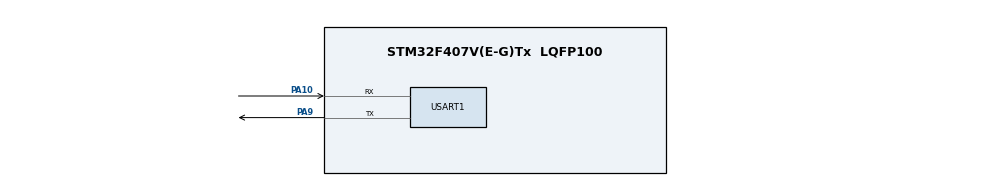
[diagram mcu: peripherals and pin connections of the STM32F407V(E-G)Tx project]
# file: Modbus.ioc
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Mcu.Family=STM32F4
Mcu.Name=STM32F407V(E-G)Tx
Mcu.Package=LQFP100
NVIC.PriorityGroup=NVIC_PRIORITYGROUP_4
NVIC.USART1_IRQn=true\:0\:0\:false\:false\:true\:true\:true\:true
PA10.Mode=Asynchronous
PA10.Signal=USART1_RX
PA13.Mode=Serial_Wire
PA13.Signal=SYS_JTMS-SWDIO
PA14.Mode=Serial_Wire
PA14.Signal=SYS_JTCK-SWCLK
PA9.Mode=Asynchronous
PA9.Signal=USART1_TX
PH0-OSC_IN.Mode=HSE-External-Oscillator
PH0-OSC_IN.Signal=RCC_OSC_IN
PH1-OSC_OUT.Mode=HSE-External-Oscillator
PH1-OSC_OUT.Signal=RCC_OSC_OUT
ProjectManager.HeapSize=0x200
ProjectManager.StackSize=0x400
ProjectManager.TargetToolchain=STM32CubeIDE
RCC.48MHZClocksFreq_Value=84000000
RCC.AHBFreq_Value=168000000
RCC.APB1CLKDivider=RCC_HCLK_DIV4
RCC.APB1Freq_Value=42000000
RCC.APB1TimFreq_Value=84000000
RCC.APB2CLKDivider=RCC_HCLK_DIV2
RCC.APB2Freq_Value=84000000
RCC.APB2TimFreq_Value=168000000
RCC.CortexFreq_Value=168000000
RCC.HCLKFreq_Value=168000000
RCC.HSE_VALUE=25000000
RCC.HSI_VALUE=16000000
RCC.LSE_VALUE=32768
RCC.PLLM=25
RCC.PLLN=336
RCC.PLLSourceVirtual=RCC_PLLSOURCE_HSE
RCC.SYSCLKFreq_VALUE=168000000
RCC.SYSCLKSource=RCC_SYSCLKSOURCE_PLLCLK
RCC.VCOOutputFreq_Value=336000000
USART1.VirtualMode=VM_ASYNC
board=custom

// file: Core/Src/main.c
/* USER CODE BEGIN Header */
/**
 ******************************************************************************
 * @file           : main.c
 * @brief          : Main program body
 ******************************************************************************
 * @attention
 *
 * Copyright (c) 2022 STMicroelectronics.
 * All rights reserved.
 *
 * This software is licensed under terms that can be found in the LICENSE file
 * in the root directory of this software component.
 * If no LICENSE file comes with this software, it is provided AS-IS.
 *
 ******************************************************************************
 */
/* USER CODE END Header */
#include "main.h"

void SystemClock_Config(void);
static void MX_GPIO_Init(void);
static void MX_USART1_UART_Init(void);
volatile int x=0;
/* USER CODE BEGIN PFP */
/* === Callback người dùng định nghĩa === */
void Timer6_Callback_1ms(void)
{
	//x++;
	  //Axis_TaskUpdate();
//    static uint8_t modbus_cnt = 0;

//    // gọi Modbus_TaskUpdate() mỗi 10 ms
//    if (++modbus_cnt >= 10)
//    {
//        modbus_cnt = 0;
//        Modbus_TaskUpdate();
//    }
    //Modbus_TaskUpdate();
    // nếu bạn muốn thêm task khác, có thể thêm ở đây
    // ví dụ:
    // if (++something >= 1000) { something = 0; blinkLED(); }
}
/* USER CODE END PFP */

int main(void)
{

  /* MCU Configuration--------------------------------------------------------*/

  /* Reset of all peripherals, Initializes the Flash interface and the Systick. */
  HAL_Init();

  /* Configure the system clock */
  SystemClock_Config();

  /* Initialize all configured peripherals */
  MX_GPIO_Init();
  MX_USART1_UART_Init();
  /* USER CODE BEGIN 2 */
  io_init();
  tim2_init();
  tim3_init();
  //TIM6_Init_1ms();
  Global_Timer_Init();
  Modbus_TaskInit(&huart1);
  /* USER CODE END 2 */

  /* Infinite loop */
  /* USER CODE BEGIN WHILE */
  Axis_Init(Holding_Registers_Database);
  HAL_Delay(1000);
  //Home_All();
  Axis_Home();
  while (1)
  {
    /* USER CODE END WHILE */
    /* USER CODE BEGIN 3 */
	  if (Task_RunEvery(1))	  Modbus_TaskUpdate();   // 1 ms
	  Axis_TaskUpdate();
  }
  /* USER CODE END 3 */
}

void SystemClock_Config(void)
{
  RCC_OscInitTypeDef RCC_OscInitStruct = {0};
  RCC_ClkInitTypeDef RCC_ClkInitStruct = {0};

  /** Configure the main internal regulator output voltage
   */
  __HAL_RCC_PWR_CLK_ENABLE();
  __HAL_PWR_VOLTAGESCALING_CONFIG(PWR_REGULATOR_VOLTAGE_SCALE1);

  /** Initializes the RCC Oscillators according to the specified parameters
   * in the RCC_OscInitTypeDef structure.
   */
  RCC_OscInitStruct.OscillatorType = RCC_OSCILLATORTYPE_HSE;
  RCC_OscInitStruct.HSEState = RCC_HSE_ON;
  RCC_OscInitStruct.PLL.PLLState = RCC_PLL_ON;
  RCC_OscInitStruct.PLL.PLLSource = RCC_PLLSOURCE_HSE;
#ifdef Tuan_board
  RCC_OscInitStruct.PLL.PLLM = 4;
  RCC_OscInitStruct.PLL.PLLN = 168;
#endif
#ifdef Chuc_board
  RCC_OscInitStruct.PLL.PLLM = 25;
  RCC_OscInitStruct.PLL.PLLN = 336;
#endif
  RCC_OscInitStruct.PLL.PLLP = RCC_PLLP_DIV2;
  RCC_OscInitStruct.PLL.PLLQ = 4;
  if (HAL_RCC_OscConfig(&RCC_OscInitStruct) != HAL_OK)
  {
    Error_Handler();
  }

  /** Initializes the CPU, AHB and APB buses clocks
   */
  RCC_ClkInitStruct.ClockType = RCC_CLOCKTYPE_HCLK | RCC_CLOCKTYPE_SYSCLK | RCC_CLOCKTYPE_PCLK1 | RCC_CLOCKTYPE_PCLK2;
  RCC_ClkInitStruct.SYSCLKSource = RCC_SYSCLKSOURCE_PLLCLK;
  RCC_ClkInitStruct.AHBCLKDivider = RCC_SYSCLK_DIV1;
  RCC_ClkInitStruct.APB1CLKDivider = RCC_HCLK_DIV4;
  RCC_ClkInitStruct.APB2CLKDivider = RCC_HCLK_DIV2;

  if (HAL_RCC_ClockConfig(&RCC_ClkInitStruct, FLASH_LATENCY_5) != HAL_OK)
  {
    Error_Handler();
  }
}

static void MX_USART1_UART_Init(void)
{

  huart1.Instance = USART1;
  huart1.Init.BaudRate = 115200;
  huart1.Init.WordLength = UART_WORDLENGTH_8B;
  huart1.Init.StopBits = UART_STOPBITS_1;
  huart1.Init.Parity = UART_PARITY_NONE;
  huart1.Init.Mode = UART_MODE_TX_RX;
  huart1.Init.HwFlowCtl = UART_HWCONTROL_NONE;
  huart1.Init.OverSampling = UART_OVERSAMPLING_16;
  if (HAL_UART_Init(&huart1) != HAL_OK)
  {
    Error_Handler();
  }
  /* USER CODE BEGIN USART1_Init 2 */
  HAL_NVIC_SetPriority(USART1_IRQn, 0, 0);
  /* USER CODE END USART1_Init 2 */
}

static void MX_GPIO_Init(void)
{

  /* GPIO Ports Clock Enable */
  __HAL_RCC_GPIOH_CLK_ENABLE();
  __HAL_RCC_GPIOA_CLK_ENABLE();

}

/* USER CODE BEGIN 4 */
// ================== IRQ Handler ==================
void TIM2_IRQHandler(void)
{
    if (TIM2->SR & TIM_SR_UIF)
    {
        TIM2->SR &= ~TIM_SR_UIF;
        if (x_steps_rem && (--x_steps_rem == 0))
        {
            Motor_Stop(AXIS_X);
        }
    }
}

void TIM3_IRQHandler(void)
{
    if (TIM3->SR & TIM_SR_UIF)
    {
        TIM3->SR &= ~TIM_SR_UIF;
        if (y_steps_rem && (--y_steps_rem == 0))
        {
            Motor_Stop(AXIS_Y);
        }
    }
}
/* USER CODE END 4 */

void Error_Handler(void)
{
  __disable_irq();
  while (1)
  {
  }
}
